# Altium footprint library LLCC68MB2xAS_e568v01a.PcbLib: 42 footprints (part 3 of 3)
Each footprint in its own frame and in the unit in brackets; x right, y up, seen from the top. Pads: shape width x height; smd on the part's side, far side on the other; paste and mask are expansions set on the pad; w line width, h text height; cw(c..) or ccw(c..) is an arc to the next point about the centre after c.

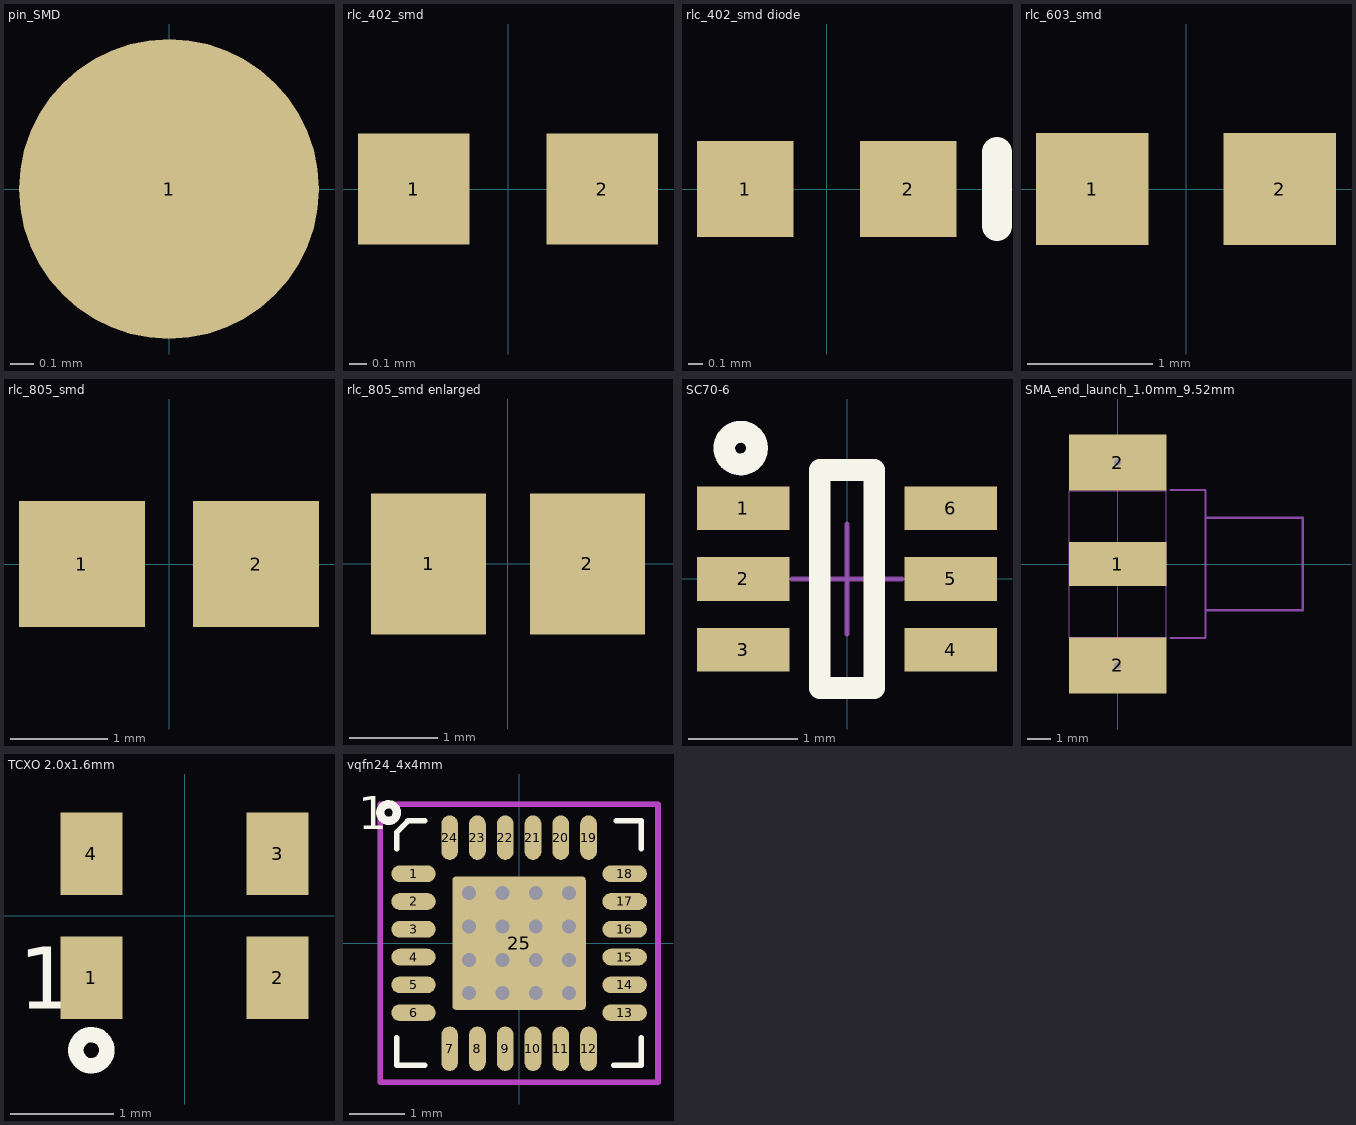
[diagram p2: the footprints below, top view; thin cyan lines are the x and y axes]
## pin_SMD [mm] "Generic Pin; 1 pin SMD"
height 0.5
pads (1):
  round 1.27 smd paste-1 mask+0.05: 1(0,0)

## rlc_402_smd [mm] "Chip SMD component 402; Body 1.0 x 0.5 mm (LxW typ)"
height 0.8
pads (2):
  rect 0.65x0.65 smd mask+0.05: 1(-0.55,0) 2(0.55,0)
3D body: height 0.8, standoff 0.2, extent -0.875,-0.325 0.875,0.325

## rlc_402_smd diode [mm] "Chip SMD component 402; Body 1.0 x 0.5 mm (LxW typ)"
height 0.8
pads (2):
  rect 0.65x0.65 smd mask+0.05: 1(-0.55,0) 2(0.55,0)
Top Overlay:
  lines w0.2: 1.15,-0.25 1.15,0.25

## rlc_603_smd [mm] "Chip SMD component 603; Body 1.6 x 0.8mm (LxW typ)"
height 1
pads (2):
  rect 0.9x0.9 smd paste+0 mask+0.05: 1(-0.75,0) 2(0.75,0)

## rlc_805_smd [mm] "Chip SMD component 805; Body 2.0 x 1.25 mm (LxW typ)"
height 1.4
pads (2):
  rect 1.3x1.3 smd mask+0.05: 1(-0.9,0) 2(0.9,0)

## rlc_805_smd enlarged [mm] "Chip SMD component 805; Body 2.0 x 1.25 mm (LxW typ)"
height 1.4
pads (2):
  rect 1.3x1.6 smd mask+0.05: 1(-0.9,0) 2(0.9,0)

## SC70-6 [mm] "SC70 6-Leads, Body 2.0x1.25mm, Pitch 0.65mm"
height 1.45
pads (6):
  rect 0.85x0.4 smd mask+0.05: 1(-0.95,0.65) 2(-0.95,0) 3(-0.95,-0.65) 4(0.95,-0.65) 5(0.95,0) 6(0.95,0.65)
Top Overlay:
  circle w0.2: c-0.975,1.2 r0.15
  lines w0.2: -0.25,-1 -0.25,1 0.25,1 0.25,-1 -0.25,-1
Mechanical 15:
  lines w0.05: -0.5,0 0.5,0 ; 0,-0.5 0,0.5
3D body: height 1.45, standoff 0, extent -0.625,-1 0.625,1

## SMA_end_launch_1.0mm_9.52mm [mm] "SMA end launch for 1.0mm PCB thickness; 9.52mm"
height 10
pads (3):
  rect 4.2x1.905 smd mask+0.05: 1(0,0)
  rect 4.2x2.413 hole 0.3 mask+0.05: 2(0,-4.38) 2(0,4.38)
Mechanical 15:
  lines w0.01: -2.1,-3.17 -2.1,3.17 2.1,3.17 2.1,-3.17 -2.1,-3.17
  lines w0.1: 2.295,-3.2 3.796,-3.2 3.796,-2 ; 2.295,3.2 3.796,3.2 3.796,2 ; 3.796,-2 3.796,2 ; 3.796,-2 8,-2 8,2 3.796,2

## TCXO 2.0x1.6mm [mm] "SMD 2.0x1.6mm for TCXO or VCTCXO"
height 1
pads (4):
  rect 0.6x0.8 smd mask+0.05: 1(-0.9,-0.6) 2(0.9,-0.6) 3(0.9,0.6) 4(-0.9,0.6)
Top Overlay:
  circle w0.15: c-0.9,-1.3 r0.15
  text "1" at -1.6,-0.9 h0.6
3D body: height 1, standoff 0, extent -1,-0.8 1,0.8

## vqfn24_4x4mm [mm] "24 Leads, Body 4.0x4.0mm, Pitch 0.50mm, VQFN24"
height 1
pads (25):
  oval 0.8x0.3 smd mask+0.05: 1(-1.9,1.25) 2(-1.9,0.75) 3(-1.9,0.25) 4(-1.9,-0.25) 5(-1.9,-0.75) 6(-1.9,-1.25) 13(1.9,-1.25) 14(1.9,-0.75) 15(1.9,-0.25) 16(1.9,0.25) 17(1.9,0.75) 18(1.9,1.25)
  oval 0.3x0.8 smd mask+0.05: 7(-1.25,-1.9) 8(-0.75,-1.9) 9(-0.25,-1.9) 10(0.25,-1.9) 11(0.75,-1.9) 12(1.25,-1.9) 19(1.25,1.9) 20(0.75,1.9) 21(0.25,1.9) 22(-0.25,1.9) 23(-0.75,1.9) 24(-1.25,1.9)
  rrect5% 2.4x2.4 smd paste-2.5 mask+0.05: 25(0,0)
via -0.3,0.3 diameter 0.5 hole 0.25
via -0.9,-0.9 diameter 0.5 hole 0.25
via -0.9,0.3 diameter 0.5 hole 0.25
via -0.9,-0.3 diameter 0.5 hole 0.25
via -0.9,0.9 diameter 0.5 hole 0.25
via -0.3,-0.3 diameter 0.5 hole 0.25
via -0.3,0.9 diameter 0.5 hole 0.25
via -0.3,-0.9 diameter 0.5 hole 0.25
via 0.3,0.9 diameter 0.5 hole 0.25
via 0.3,0.3 diameter 0.5 hole 0.25
via 0.9,0.9 diameter 0.5 hole 0.25
via 0.9,0.3 diameter 0.5 hole 0.25
via 0.9,-0.3 diameter 0.5 hole 0.25
via 0.9,-0.9 diameter 0.5 hole 0.25
via 0.3,-0.9 diameter 0.5 hole 0.25
via 0.3,-0.3 diameter 0.5 hole 0.25
Top Overlay:
  circle w0.15: c-2.35,2.35 r0.15
  lines w0.1: -2.2,-1.7 -2.2,-2.2 -1.7,-2.2 ; -2.2,1.7 -2.2,2 -2,2.2 -1.7,2.2 ; 1.7,-2.2 2.2,-2.2 2.2,-1.7 ; 1.75,2.2 2.2,2.2 2.2,1.7
  text "1" at -2.9,2.05 h0.6
Top Paste:
  region: -1.15,-1.15 -0.05,-1.15 -0.05,-0.05 -1.15,-0.05
  region: -1.15,0.05 -0.05,0.05 -0.05,1.15 -1.15,1.15
  region: 0.05,0.05 1.15,0.05 1.15,1.15 0.05,1.15
  region: 0.05,-1.15 1.15,-1.15 1.15,-0.05 0.05,-0.05
Mechanical 15 keep-out:
  lines w0.1: -2.5,-2.5 2.5,-2.5 2.5,2.5 -2.5,2.5 -2.5,-2.5
3D body: height 1, standoff 0.05, extent -2,-2 2,2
